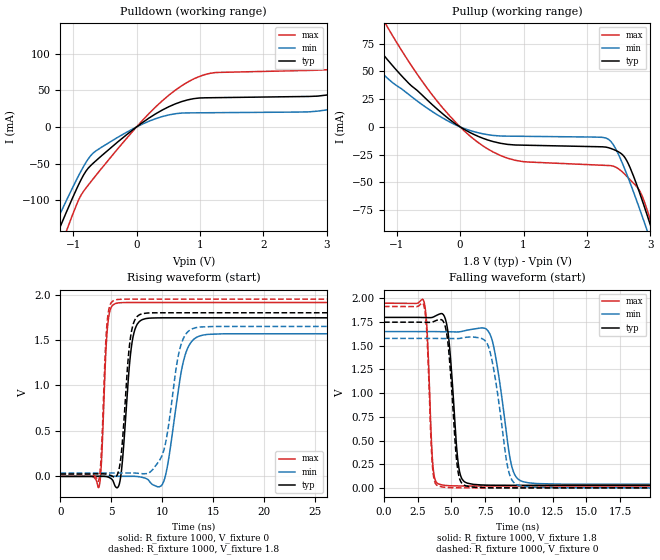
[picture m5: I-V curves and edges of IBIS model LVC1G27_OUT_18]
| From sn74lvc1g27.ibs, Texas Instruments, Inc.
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[Model]   LVC1G27_OUT_18
Model_type  Output
Vref =   0
Rref =   1000
Cref =   30p
Vmeas =   0.9
| variable   typ   min   max
C_comp   8.96pF   6.63pF   13.09pF
| C_pullup   8.25pF   6.63pF   8.86pF
| C_pulldown   9.66pF   6.76pF   13.09pF
[Temperature Range]   40   100   -40
| Ambient temperature   25   85   -40
[Voltage range]   1.8   1.65   1.95
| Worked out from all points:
|   slope of the pulldown table from 0 to 0.27 V, typ, clamps not added: 16.6 ohm
|   slope of the pullup table from 0 to 0.27 V, typ, clamps not added: 33.2 ohm
|   rising waveform, R_fixture 1000, V_fixture 0: 20-80 % time 721ps typ, 1.26ns min, 425ps max; typ from 0 V to 1.74 V
|   falling waveform, R_fixture 1000, V_fixture 1.8: 20-80 % time 526ps typ, 942ps min, 318ps max; typ from 1.8 V to 0.027 V
|   rising waveform, R_fixture 1000, V_fixture 1.8: 20-80 % time 703ps typ, 1.27ns min, 420ps max; typ from 0.027 V to 1.8 V
|   falling waveform, R_fixture 1000, V_fixture 0: 20-80 % time 517ps typ, 929ps min, 313ps max; typ from 1.75 V to 0 V
[Pulldown]
| LVC1G27_OUT_18
|   Voltage   I(typ)   I(min)   I(max)
-5.5V     -1.024A    -932.8mA   -1.173A
-1.44V    -185.2mA   -162.4mA   -222.4mA
-1.105V   -116mA     -100.2mA   -142mA
-645mV    -46.52mA   -32.98mA   -66.62mA
805mV     36.94mA    19.18mA    61.21mA
3.215V    47.58mA    27.05mA    81.88mA
4.145V    78.53mA    21.52mA    125.4mA
4.31V     68.9mA     21.59mA    136.1mA
4.47V     45.47mA    21.68mA    146.3mA
4.7V      44.48mA    21.82mA    139.5mA
5.01V     44.71mA    22mA       83.15mA
11V       50.72mA    25.33mA    93.05mA
[Pullup]
| LVC1G27_OUT_18
|   Voltage   I(typ)   I(min)   I(max)
-5.5V     476.4mA    372.8mA    667mA
-1.985V   124.4mA    93.02mA    180.5mA
-1.605V   93.94mA    69.4mA     137.6mA
-1.145V   60.57mA    43.87mA    89.95mA
-350mV    15.5mA     10.6mA     22.36mA
440mV     -11.85mA   -7.028mA   -20.01mA
2.34V     -18.76mA   -11.2mA    -34.79mA
2.625V    -30.23mA   -42.31mA   -44.38mA
2.93V     -76.38mA   -90.38mA   -71.68mA
3.03V     -93.86mA   -107.1mA   -89.69mA
3.115V    -109.1mA   -121.5mA   -106mA
11V       -1.709A    -1.61A     -1.886A
[Ramp]
| LVC1G27_OUT_18
| variable   typ   min   max
dV/dt_r   1.12/7.66E-10   1.01/1.34E-09   1.22/4.54E-10
dV/dt_f   1.09/5.45E-10   0.99/9.72E-10   1.18/3.32E-10
R_load = 1000
[Rising Waveform]
| LVC1G27_OUT_18
R_fixture =   1000
C_fixture =   0
L_fixture =   0
V_fixture =   0
V_fixture_min = 0
V_fixture_max = 0
|   Time   V(typ)   V(min)   V(max)
0s        112.7pV    7.663nV    2.84nV
3.79ns    907.9uV    -55.33uV   -115.1mV
4.615ns   -4.964mV   69.35uV    1.634V
5.36ns    -105.5mV   661uV      1.899V
5.97ns    41.22mV    637.6uV    1.911V
7.045ns   1.481V     749.8uV    1.913V
8.035ns   1.724V     -10.81mV   1.913V
10.12ns   1.744V     -61.57mV   1.913V
13.58ns   1.744V     1.541V     1.913V
43ns      1.744V     1.569V     1.913V
[Falling Waveform]
| LVC1G27_OUT_18
R_fixture =   1000
C_fixture =   0
L_fixture =   0
V_fixture =   1.8
V_fixture_min = 1.65
V_fixture_max = 1.95
|   Time   V(typ)   V(min)   V(max)
0s        1.8V       1.65V      1.95V
2.95ns    1.798V     1.65V      1.973V
3.62ns    1.802V     1.65V      243.3mV
4.11ns    1.835V     1.649V     37.94mV
4.755ns   1.632V     1.648V     23.42mV
5.56ns    201.6mV    1.647V     20.29mV
6.185ns   49.47mV    1.666V     19.87mV
7.95ns    28.06mV    1.59V      19.73mV
10.31ns   27.02mV    65.2mV     19.73mV
43ns      26.97mV    37.14mV    19.72mV
[Rising Waveform]
| LVC1G27_OUT_18
R_fixture =   1000
C_fixture =   0
L_fixture =   0
V_fixture =   1.8
V_fixture_min = 1.65
V_fixture_max = 1.95
|   Time   V(typ)   V(min)   V(max)
0s        26.95mV    37.1mV     19.71mV
3.76ns    27.74mV    37.06mV    -43.55mV
4.565ns   23.56mV    37.17mV    1.671V
5.275ns   -10.64mV   37.63mV    1.937V
5.935ns   208mV      37.44mV    1.948V
6.915ns   1.554V     37.14mV    1.95V
7.83ns    1.782V     31.59mV    1.95V
10.05ns   1.8V       250.7mV    1.95V
12.97ns   1.8V       1.625V     1.95V
43ns      1.8V       1.65V      1.95V
[Falling Waveform]
| LVC1G27_OUT_18
R_fixture =   1000
C_fixture =   0
L_fixture =   0
V_fixture =   0
V_fixture_min = 0
V_fixture_max = 0
|   Time   V(typ)   V(min)   V(max)
0s        1.749V     1.578V     1.916V
2.95ns    1.748V     1.578V     1.928V
3.595ns   1.751V     1.578V     222.5mV
4.025ns   1.774V     1.578V     19.13mV
4.65ns    1.628V     1.577V     4.167mV
5.435ns   224.1mV    1.576V     664.6uV
6.075ns   21.11mV    1.59V      177.4uV
7.75ns    1.155mV    1.49V      23.43uV
10ns      61.33uV    24.61mV    17.41uV
43ns      16.05uV    30.81uV    8.873uV
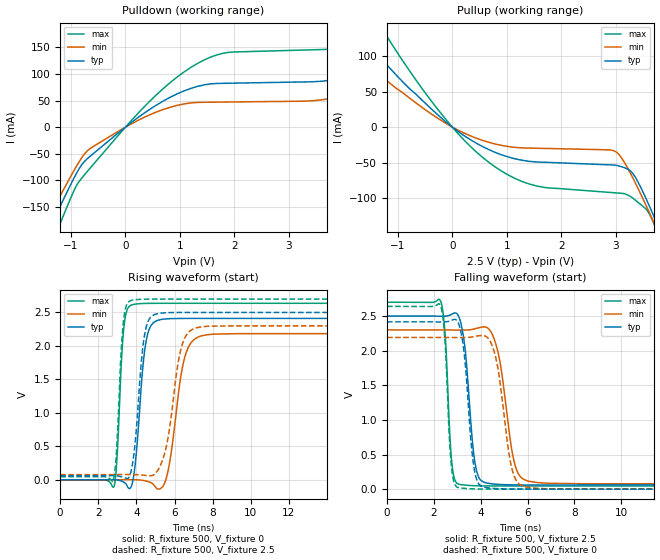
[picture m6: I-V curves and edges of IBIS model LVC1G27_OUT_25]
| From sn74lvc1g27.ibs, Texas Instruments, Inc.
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[Model]   LVC1G27_OUT_25
Model_type  Output
Vref =   0
Rref =   500
Cref =   30p
Vmeas =   1.25
| variable   typ   min   max
C_comp   8.68pF   6.48pF   11.63pF
| C_pullup   8.47pF   6.48pF   9.44pF
| C_pulldown   8.89pF   6.52pF   11.63pF
[Temperature Range]   40   100   -40
| Ambient temperature   25   85   -40
[Voltage range]   2.5   2.3   2.7
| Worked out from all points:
|   slope of the pulldown table from 0 to 0.375 V, typ, clamps not added: 13.1 ohm
|   slope of the pullup table from 0 to 0.375 V, typ, clamps not added: 19.1 ohm
|   rising waveform, R_fixture 500, V_fixture 0: 20-80 % time 412ps typ, 624ps min, 270ps max; typ from 0 V to 2.41 V
|   falling waveform, R_fixture 500, V_fixture 2.5: 20-80 % time 352ps typ, 538ps min, 225ps max; typ from 2.5 V to 0.06 V
|   rising waveform, R_fixture 500, V_fixture 2.5: 20-80 % time 419ps typ, 673ps min, 272ps max; typ from 0.06 V to 2.5 V
|   falling waveform, R_fixture 500, V_fixture 0: 20-80 % time 342ps typ, 515ps min, 221ps max; typ from 2.42 V to 0 V
[Pulldown]
| LVC1G27_OUT_25
|   Voltage   I(typ)   I(min)   I(max)
-5.5V     -1.065A    -962.2mA   -1.233A
-1.515V   -217.8mA   -190.9mA   -261.5mA
-1.145V   -137.3mA   -118.9mA   -167.6mA
-660mV    -55.79mA   -41.12mA   -78.48mA
535mV     39.4mA     27.09mA    57.66mA
1.455V    79.8mA     46.83mA    127mA
3.83V     89.86mA    55.41mA    148.1mA
5.34V     157.5mA    105.9mA    231.7mA
5.91V     188.7mA    52.63mA    283.1mA
6.525V    93.57mA    53.14mA    299.2mA
7.56V     94.12mA    54.12mA    161mA
11V       99.65mA    57.57mA    169.2mA
[Pullup]
| LVC1G27_OUT_25
|   Voltage   I(typ)   I(min)   I(max)
-5.5V     548.1mA    433.4mA    764.5mA
-2.31V    190.8mA    146mA      272.9mA
-1.86V    147mA      111.5mA    211.6mA
-1.295V   95.71mA    71.6mA     139.1mA
-180mV    11.41mA    8.219mA    16.71mA
710mV     -33.04mA   -22.25mA   -51.89mA
1.555V    -49.16mA   -29.78mA   -83.08mA
2.995V    -53.63mA   -34.3mA    -92.61mA
3.34V     -67.98mA   -75.27mA   -101.5mA
3.565V    -101.9mA   -111.4mA   -116.1mA
3.76V     -136.1mA   -144.4mA   -146.6mA
11V       -1.614A    -1.516A    -1.796A
[Ramp]
| LVC1G27_OUT_25
| variable   typ   min   max
dV/dt_r   1.53/4.39E-10   1.39/6.63E-10   1.65/2.84E-10
dV/dt_f   1.49/3.69E-10   1.36/5.56E-10   1.62/2.34E-10
R_load = 500
[Rising Waveform]
| LVC1G27_OUT_25
R_fixture =   500
C_fixture =   0
L_fixture =   0
V_fixture =   0
V_fixture_min = 0
V_fixture_max = 0
|   Time   V(typ)   V(min)   V(max)
0s        123.5pV    5.747nV    2.547nV
2.83ns    1.886mV    120uV      -101.9mV
3.335ns   -34.99mV   1.188mV    2.256V
3.815ns   -10.33mV   1.485mV    2.618V
4.485ns   2.031V     -16.83mV   2.635V
5.18ns    2.387V     -140.2mV   2.637V
5.685ns   2.406V     168.5mV    2.637V
6.535ns   2.41V      1.831V     2.637V
7.42ns    2.411V     2.151V     2.637V
34.99ns   2.411V     2.183V     2.637V
[Falling Waveform]
| LVC1G27_OUT_25
R_fixture =   500
C_fixture =   0
L_fixture =   0
V_fixture =   2.5
V_fixture_min = 2.3
V_fixture_max = 2.7
|   Time   V(typ)   V(min)   V(max)
0s        2.5V       2.3V       2.7V
2.305ns   2.498V     2.3V       2.706V
2.765ns   2.527V     2.299V     388.8mV
3.08ns    2.48V      2.297V     70.33mV
3.76ns    374.5mV    2.317V     49.54mV
4.23ns    91.26mV    2.341V     46.81mV
4.77ns    68.77mV    1.931V     45.99mV
5.47ns    61.91mV    344.7mV    45.74mV
6.1ns     60.6mV     111.4mV    45.69mV
34.99ns   60.09mV    77.08mV    45.62mV
[Rising Waveform]
| LVC1G27_OUT_25
R_fixture =   500
C_fixture =   0
L_fixture =   0
V_fixture =   2.5
V_fixture_min = 2.3
V_fixture_max = 2.7
|   Time   V(typ)   V(min)   V(max)
0s        60.06mV    77.04mV    45.59mV
2.775ns   61.81mV    77.11mV    -13.17mV
3.305ns   37.51mV    78.02mV    2.325V
3.72ns    129.3mV    78.11mV    2.68V
4.41ns    2.134V     67.59mV    2.698V
5.035ns   2.477V     108.9mV    2.7V
5.595ns   2.496V     532.2mV    2.7V
6.375ns   2.5V       1.994V     2.7V
7.175ns   2.5V       2.273V     2.7V
34.99ns   2.5V       2.3V       2.7V
[Falling Waveform]
| LVC1G27_OUT_25
R_fixture =   500
C_fixture =   0
L_fixture =   0
V_fixture =   0
V_fixture_min = 0
V_fixture_max = 0
|   Time   V(typ)   V(min)   V(max)
0s        2.416V     2.191V     2.64V
2.3ns     2.414V     2.192V     2.636V
2.75ns    2.439V     2.19V      329.8mV
3.075ns   2.373V     2.19V      20.16mV
3.71ns    319.5mV    2.204V     3.962mV
4.19ns    26.07mV    2.212V     1.181mV
4.685ns   8.294mV    1.836V     420.7uV
5.355ns   1.873mV    269mV      155uV
5.925ns   600.8uV    32.07mV    99.81uV
34.99ns   27.73uV    35.22uV    20.22uV
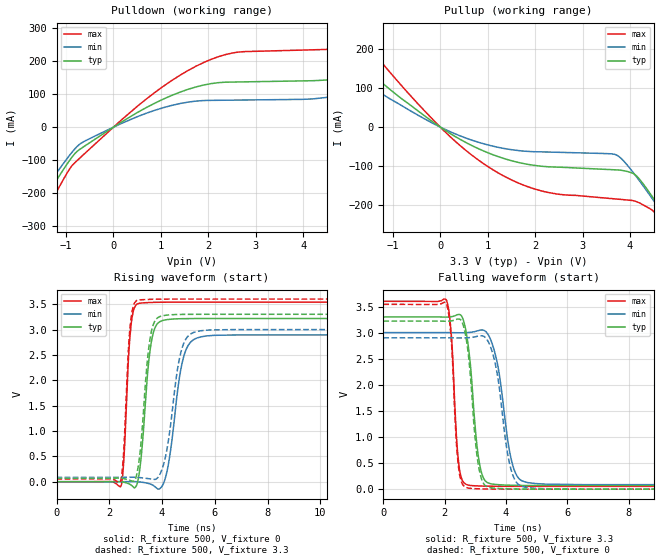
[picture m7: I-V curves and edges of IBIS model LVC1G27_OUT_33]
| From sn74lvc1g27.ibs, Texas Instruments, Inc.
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[Model]   LVC1G27_OUT_33
Model_type  Output
Vref =   0
Rref =   500
Cref =   50p
Vmeas =   1.5
| variable   typ   min   max
C_comp   8.37pF   6.24pF   10.52pF
| C_pullup   8.48pF   6.24pF   9.74pF
| C_pulldown   8.25pF   6.34pF   10.52pF
[Temperature Range]   40   100   -40
| Ambient temperature   25   85   -40
[Voltage range]   3.3   3   3.6
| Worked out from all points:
|   slope of the pulldown table from 0 to 0.495 V, typ, clamps not added: 11.3 ohm
|   slope of the pullup table from 0 to 0.495 V, typ, clamps not added: 13.5 ohm
|   rising waveform, R_fixture 500, V_fixture 0: 20-80 % time 306ps typ, 439ps min, 199ps max; typ from 0 V to 3.22 V
|   falling waveform, R_fixture 500, V_fixture 3.3: 20-80 % time 289ps typ, 421ps min, 189ps max; typ from 3.3 V to 0.069 V
|   rising waveform, R_fixture 500, V_fixture 3.3: 20-80 % time 308ps typ, 461ps min, 199ps max; typ from 0.069 V to 3.3 V
|   falling waveform, R_fixture 500, V_fixture 0: 20-80 % time 282ps typ, 405ps min, 187ps max; typ from 3.22 V to 0 V
[Pulldown]
| LVC1G27_OUT_33
|   Voltage   I(typ)   I(min)   I(max)
-5.5V     -1.112A    -993.8mA   -1.301A
-2.095V   -365.2mA   -321.2mA   -435.6mA
-1.48V    -224.6mA   -195.7mA   -271.3mA
-705mV    -67mA      -50.96mA   -93.4mA
1.895V    127.7mA    80.8mA     195.8mA
4.735V    148.3mA    96.37mA    238.3mA
6.005V    208mA      150.5mA    305.3mA
6.98V     278.7mA    201.6mA    397mA
7.35V     308.5mA    129.4mA    437.6mA
7.84V     330.1mA    92.52mA    494.8mA
8.75V     170.8mA    93.27mA    501.3mA
11V       160mA      96.49mA    277.5mA
[Pullup]
| LVC1G27_OUT_33
|   Voltage   I(typ)   I(min)   I(max)
-5.5V     620.3mA    489.5mA    867.8mA
-3.245V   338.6mA    262.4mA    480.1mA
-2.5V     251.3mA    193mA      358.8mA
-1.96V    190.8mA    145.3mA    273.9mA
-50mV     4.153mA    3.023mA    6.162mA
1.115V    -70.96mA   -48.91mA   -109.6mA
2.135V    -100.3mA   -63.39mA   -163.5mA
3.715V    -109.6mA   -71.54mA   -184.3mA
4.15V     -126.7mA   -129.5mA   -191.7mA
4.79V     -237.7mA   -240mA     -270mA
4.985V    -275.2mA   -275.3mA   -310.9mA
11V       -1.523A    -1.428A    -1.714A
[Ramp]
| LVC1G27_OUT_33
| variable   typ   min   max
dV/dt_r   2.00/3.23E-10   1.82/4.64E-10   2.18/2.08E-10
dV/dt_f   1.96/3.05E-10   1.78/4.36E-10   2.15/1.98E-10
R_load = 500
[Rising Waveform]
| LVC1G27_OUT_33
R_fixture =   500
C_fixture =   0
L_fixture =   0
V_fixture =   0
V_fixture_min = 0
V_fixture_max = 0
|   Time   V(typ)   V(min)   V(max)
0s        141.8pV    4.978nV    2.433nV
2.44ns    1.239mV    280.8uV    -85.02mV
2.55ns    -8.613mV   790.6uV    419.7mV
2.815ns   -61.71mV   2.613mV    3.037V
3.13ns    148.9mV    -2.822mV   3.517V
3.59ns    2.74V      -52.04mV   3.533V
4.09ns    3.186V     13.88mV    3.538V
4.8ns     3.213V     2.424V     3.539V
5.48ns    3.216V     2.856V     3.539V
28.99ns   3.216V     2.894V     3.539V
[Falling Waveform]
| LVC1G27_OUT_33
R_fixture =   500
C_fixture =   0
L_fixture =   0
V_fixture =   3.3
V_fixture_min = 3
V_fixture_max = 3.6
|   Time   V(typ)   V(min)   V(max)
0s        3.3V       3V         3.6V
2.05ns    3.297V     3V         3.632V
2.225ns   3.306V     2.999V     2.886V
2.465ns   3.346V     2.997V     454.9mV
2.79ns    2.645V     3.003V     74.85mV
3.265ns   212.8mV    3.047V     58.69mV
3.705ns   88.15mV    2.445V     55.41mV
4.22ns    74.2mV     456mV      54.41mV
4.71ns    70.79mV    125.8mV    54.14mV
28.99ns   69.38mV    85.91mV    53.97mV
[Rising Waveform]
| LVC1G27_OUT_33
R_fixture =   500
C_fixture =   0
L_fixture =   0
V_fixture =   3.3
V_fixture_min = 3
V_fixture_max = 3.6
|   Time   V(typ)   V(min)   V(max)
0s        69.35mV    85.87mV    53.95mV
2.42ns    71.38mV    86.1mV     -4.604mV
2.54ns    62.27mV    86.6mV     544.6mV
2.785ns   28.14mV    88.21mV    3.029V
3.065ns   202.7mV    85.62mV    3.577V
3.54ns    2.798V     57.1mV     3.594V
4.005ns   3.269V     253.3mV    3.599V
4.715ns   3.297V     2.551V     3.6V
5.335ns   3.3V       2.963V     3.6V
28.99ns   3.3V       3V         3.6V
[Falling Waveform]
| LVC1G27_OUT_33
R_fixture =   500
C_fixture =   0
L_fixture =   0
V_fixture =   0
V_fixture_min = 0
V_fixture_max = 0
|   Time   V(typ)   V(min)   V(max)
0s        3.22V      2.9V       3.542V
2.05ns    3.218V     2.9V       3.565V
2.215ns   3.225V     2.899V     2.849V
2.455ns   3.259V     2.898V     403.1mV
2.785ns   2.505V     2.903V     19.1mV
3.22ns    166.2mV    2.939V     4.918mV
3.645ns   18.46mV    2.417V     1.566mV
4.17ns    4.741mV    362.4mV    478.5uV
4.625ns   1.524mV    38.25mV    206.4uV
28.99ns   24.69uV    29.25uV    20.19uV
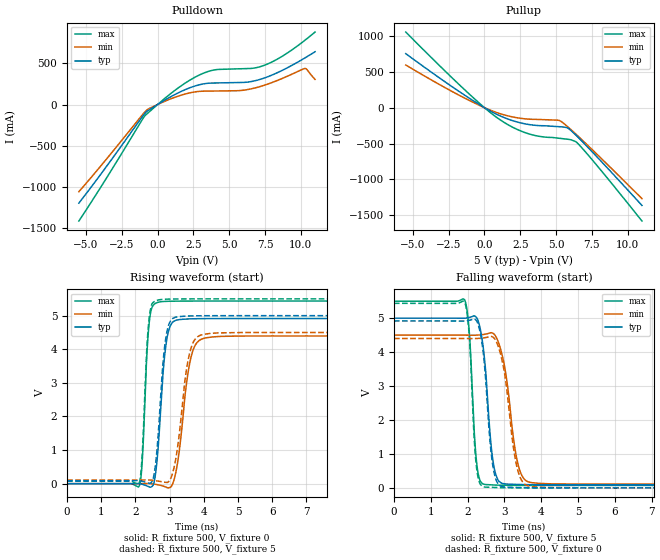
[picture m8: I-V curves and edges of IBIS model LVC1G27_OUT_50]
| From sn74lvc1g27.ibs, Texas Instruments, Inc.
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[Model]   LVC1G27_OUT_50
Model_type  Output
Vref =   0
Rref =   500
Cref =   50p
Vmeas =   2.5
| variable   typ   min   max
C_comp   7.88pF   5.92pF   9.56pF
| C_pullup   8.30pF   5.92pF   9.56pF
| C_pulldown   7.45pF   6.07pF   9.35pF
[Temperature Range]   40   100   -40
| Ambient temperature   25   85   -40
[Voltage range]   5   4.5   5.5
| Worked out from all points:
|   slope of the pulldown table from 0 to 0.75 V, typ, clamps not added: 9.58 ohm
|   slope of the pullup table from 0 to 0.75 V, typ, clamps not added: 9.16 ohm
|   rising waveform, R_fixture 500, V_fixture 0: 20-80 % time 211ps typ, 306ps min, 144ps max; typ from 0 V to 4.91 V
|   falling waveform, R_fixture 500, V_fixture 5: 20-80 % time 218ps typ, 317ps min, 154ps max; typ from 5 V to 0.09 V
|   rising waveform, R_fixture 500, V_fixture 5: 20-80 % time 212ps typ, 313ps min, 144ps max; typ from 0.09 V to 5 V
|   falling waveform, R_fixture 500, V_fixture 0: 20-80 % time 215ps typ, 311ps min, 147ps max; typ from 4.92 V to 0 V
[Pulldown]
| LVC1G27_OUT_50
|   Voltage   I(typ)   I(min)   I(max)
-5.5V     -1.198A    -1.059A    -1.415A
-940mV    -118.4mA   -100.1mA   -148.6mA
-645mV    -71.01mA   -53.56mA   -98.24mA
800mV     83.29mA    61.2mA     116.9mA
2.295V    206.2mA    143.4mA    300.5mA
3.555V    259mA      163mA      402.9mA
5.915V    268.2mA    172.5mA    435.1mA
6.785V    288mA      200.6mA    444mA
7.565V    329.2mA    240.8mA    484mA
8.805V    423.4mA    324.2mA    597mA
10.28V    565mA      437.4mA    779.4mA
11V       641.2mA    305.2mA    880.8mA
[Pullup]
| LVC1G27_OUT_50
|   Voltage   I(typ)   I(min)   I(max)
-5.5V     752.7mA    594.4mA    1.054A
-1.36V    171.1mA    130.8mA    245.1mA
125mV     -14.77mA   -11.04mA   -21.53mA
1.015V    -107mA     -78.37mA   -158.2mA
2.025V    -184.2mA   -131mA     -278mA
3.04V     -232.4mA   -158.5mA   -360.7mA
3.945V    -250.5mA   -165.3mA   -402.5mA
5.3V      -265.9mA   -185.4mA   -427.7mA
5.83V     -285.1mA   -268.2mA   -440mA
6.53V     -411.2mA   -395.2mA   -500.3mA
8.1V      -736mA     -695.6mA   -863mA
11V       -1.361A    -1.267A    -1.578A
[Ramp]
| LVC1G27_OUT_50
| variable   typ   min   max
dV/dt_r   3.01/2.20E-10   2.71/3.22E-10   3.32/1.51E-10
dV/dt_f   2.99/2.27E-10   2.68/3.30E-10   3.30/1.62E-10
R_load = 500
[Rising Waveform]
| LVC1G27_OUT_50
R_fixture =   500
C_fixture =   0
L_fixture =   0
V_fixture =   0
V_fixture_min = 0
V_fixture_max = 0
|   Time   V(typ)   V(min)   V(max)
0s        181.8pV    4.248nV    2.382nV
2.12ns    -565.6uV   359.4uV    -49.73mV
2.405ns   -97.08mV   3.48mV     4.81V
2.69ns    1.432V     -39.81mV   5.405V
2.845ns   3.717V     -83.57mV   5.423V
3.01ns    4.678V     -111.5mV   5.429V
3.235ns   4.874V     639mV      5.432V
3.625ns   4.906V     3.761V     5.435V
4.085ns   4.913V     4.344V     5.435V
24.99ns   4.914V     4.397V     5.435V
[Falling Waveform]
| LVC1G27_OUT_50
R_fixture =   500
C_fixture =   0
L_fixture =   0
V_fixture =   5
V_fixture_min = 4.5
V_fixture_max = 5.5
|   Time   V(typ)   V(min)   V(max)
0s        5V         4.5V       5.5V
1.925ns   4.999V     4.499V     5.535V
2.05ns    5.022V     4.498V     4.559V
2.25ns    5.011V     4.5V       713.3mV
2.475ns   3.646V     4.527V     98.58mV
2.65ns    1.147V     4.57V      87.68mV
2.8ns     297.7mV    4.393V     80.47mV
3.365ns   100.2mV    722.7mV    72.98mV
3.75ns    93.02mV    152.6mV    71.95mV
24.99ns   89.63mV    107.6mV    71.34mV
[Rising Waveform]
| LVC1G27_OUT_50
R_fixture =   500
C_fixture =   0
L_fixture =   0
V_fixture =   5
V_fixture_min = 4.5
V_fixture_max = 5.5
|   Time   V(typ)   V(min)   V(max)
0s        89.62mV    107.6mV    71.33mV
2.105ns   91.13mV    107.8mV    19.61mV
2.19ns    74.24mV    108.9mV    738.8mV
2.4ns     12.94mV    111.1mV    4.913V
2.685ns   1.749V     73.55mV    5.471V
2.83ns    3.857V     47.76mV    5.487V
2.985ns   4.761V     79.53mV    5.494V
3.58ns    4.991V     3.862V     5.499V
4.005ns   4.998V     4.447V     5.5V
24.99ns   5V         4.5V       5.5V
[Falling Waveform]
| LVC1G27_OUT_50
R_fixture =   500
C_fixture =   0
L_fixture =   0
V_fixture =   0
V_fixture_min = 0
V_fixture_max = 0
|   Time   V(typ)   V(min)   V(max)
0s        4.917V     4.401V     5.437V
1.925ns   4.917V     4.4V       5.464V
2.05ns    4.939V     4.399V     4.444V
2.235ns   4.935V     4.4V       688.5mV
2.47ns    3.499V     4.425V     22.83mV
2.63ns    1.144V     4.463V     15.72mV
2.78ns    221mV      4.311V     9.051mV
3.335ns   10.45mV    647.5mV    1.654mV
3.67ns    3.893mV    50.44mV    707.5uV
24.99ns   11.22uV    15.13uV    10.6uV
